VERSION 5.8 ;
BUSBITCHARS "[]" ;
DIVIDERCHAR "/" ;

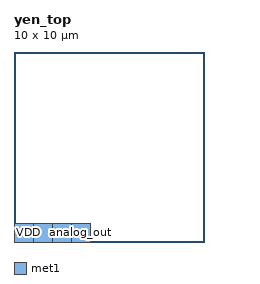
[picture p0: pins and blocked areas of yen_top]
MACRO yen_top
  CLASS BLOCK ;
  ORIGIN 0 0 ;
  SIZE 10 BY 10 ;

  PIN VDD
    DIRECTION INOUT ;
    USE POWER ;
    PORT
      LAYER met1 ;
      RECT 0 0 1 1 ;
    END
  END VDD

  PIN VSS
    DIRECTION INOUT ;
    USE GROUND ;
    PORT
      LAYER met1 ;
      RECT 1 0 2 1 ;
    END
  END VSS

  PIN analog_in
    DIRECTION INPUT ;
    PORT
      LAYER met1 ;
      RECT 2 0 3 1 ;
    END
  END analog_in

  PIN analog_out
    DIRECTION OUTPUT ;
    PORT
      LAYER met1 ;
      RECT 3 0 4 1 ;
    END
  END analog_out

END yen_top

END LIBRARY
